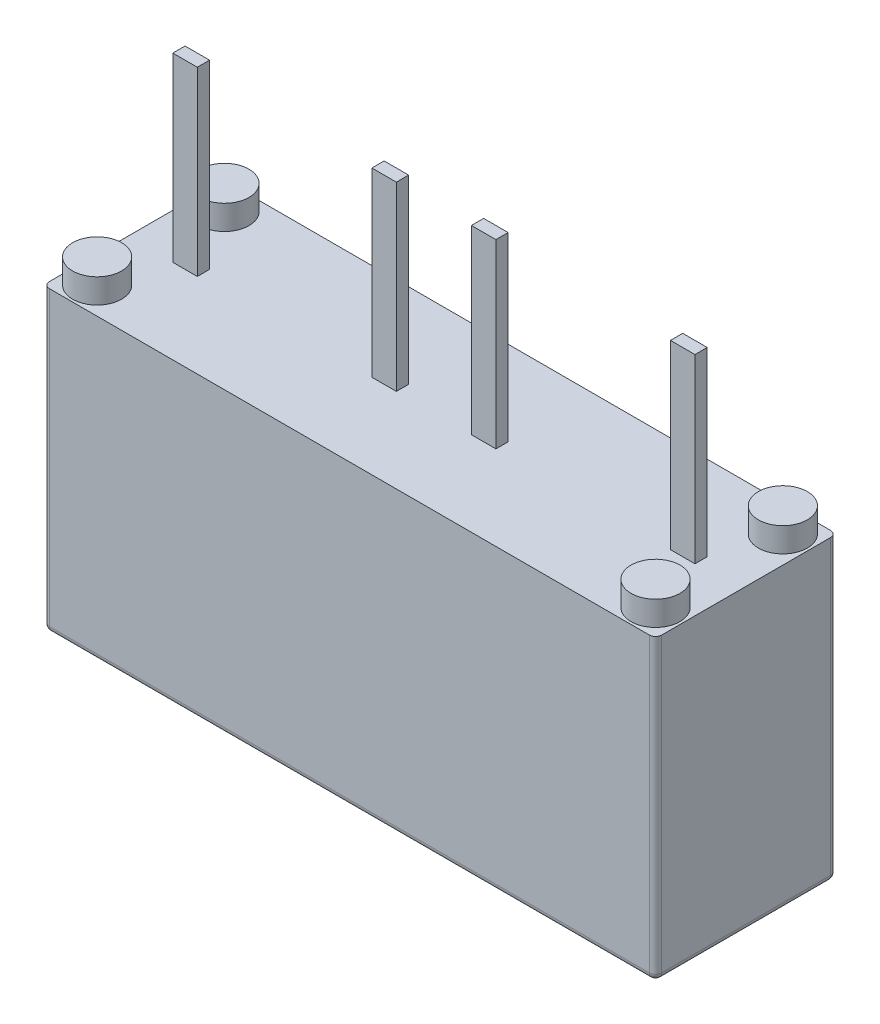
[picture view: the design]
from build123d import *

# Parameters (mm, degrees)
SKETCH1_W               = 12.5
SKETCH1_H               = 3.7
BOSS_EXTRUDE1_DEPTH     = 3.05
FILLET1_R               = 0.127
SKETCH12_R              = 0.625
BOSS_EXTRUDE8_DEPTH     = 0.001
SKETCH14_W              = 0.155844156
SKETCH14_H              = 1
BOSS_EXTRUDE10_DEPTH    = 0.001
SKETCH15_W              = 0.315584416
SKETCH15_H              = 0.175324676
SKETCH15_W_2            = 0.315584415
PART_NUMBER_DEPTH       = 0.001
SKETCH2_R               = 0.5
BOSS_EXTRUDE11_DEPTH    = 0.5
MIRROR2_COPY_1_SKETCH_R = 0.5
MIRROR2_COPY_1_DEPTH    = 0.5
SKETCH16_W              = 0.5
SKETCH16_H              = 0.25
BOSS_EXTRUDE12_DEPTH    = 3.7


with BuildPart() as part:
    # Sketch1 → Boss-Extrude1 (new, symmetric)
    with BuildSketch(Plane(origin=(0, 0, 0), x_dir=(1, 0, 0), z_dir=(0, 1, 0))):
        Rectangle(SKETCH1_W, SKETCH1_H)
    extrude(amount=BOSS_EXTRUDE1_DEPTH, both=True)

    # Fillet1
    fillet1_edges = [part.edges().sort_by_distance(p)[0] for p in [
        (0, -3.05, 1.85),
        (-6.25, -3.05, 0),
        (0, -3.05, -1.85),
        (6.25, -3.05, 0),
        (6.25, 0, 1.85),
        (-6.25, 0, 1.85),
        (-6.25, 0, -1.85),
        (6.25, 0, -1.85),
    ]]
    fillet(fillet1_edges, radius=FILLET1_R)

    # Sketch12 → Boss-Extrude8 (add)
    with BuildSketch(Plane(origin=(0, -3.05, 0), x_dir=(-1, 0, 0), z_dir=(0, -1, 0))):
        with Locations(Location((5.337664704, 0.725256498, 0), (0, 0, 270))):
            Circle(SKETCH12_R)
        Polygon((-4.767808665, 0.401887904), (-5.208078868, -1.480706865), (-5.548883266, -1.401005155), (-5.270390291, -0.21016959), (-5.767010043, -0.559917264), (-5.406669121, 0.980900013), (-5.650100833, 1.037829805), (-5.134766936, 1.287763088), (-4.82243301, 0.844268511), (-5.065864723, 0.901198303), (-5.264428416, 0.05214023), align=None)
    extrude(amount=BOSS_EXTRUDE8_DEPTH)

    # Sketch14 → Boss-Extrude10 (add)
    # profile 1 of 14: a face of its own
    with BuildSketch(Plane.XZ.offset(3.05)):
        with BuildLine():
            Line((-5.930411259, 0.573168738), (-5.930411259, 1.573168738))
            Line((-5.930411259, 1.573168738), (-5.66093074, 1.573168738))
            add(Edge.make_bspline(
                [(-5.66093074, 1.573168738), (-5.648958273, 1.573126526), (-5.626026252, 1.573045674), (-5.593279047, 1.572530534), (-5.563717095, 1.571269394), (-5.537463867, 1.569706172), (-5.514446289, 1.567732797), (-5.494757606, 1.565290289), (-5.478210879, 1.562725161), (-5.468474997, 1.559990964), (-5.464096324, 1.558761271)],
                knots=[0, 0, 0, 0, 1.45237712, 2.781878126, 3.972677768, 5.041396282, 5.972228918, 6.774219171, 7.448710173, 8, 8, 8, 8], degree=3))
            add(Edge.make_bspline(
                [(-5.464096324, 1.558761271), (-5.458035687, 1.556632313), (-5.445976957, 1.552396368), (-5.428545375, 1.544172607), (-5.411950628, 1.534267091), (-5.396234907, 1.522581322), (-5.381384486, 1.509322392), (-5.36727424, 1.494433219), (-5.354210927, 1.477745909), (-5.341744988, 1.459658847), (-5.330429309, 1.440110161), (-5.320602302, 1.419076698), (-5.312610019, 1.396588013), (-5.305600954, 1.372856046), (-5.300392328, 1.347670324), (-5.296808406, 1.321155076), (-5.294527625, 1.293311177), (-5.294210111, 1.274269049), (-5.294047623, 1.264524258)],
                knots=[0, 0, 0, 0, 0.846149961, 1.683567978, 2.535100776, 3.389102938, 4.260422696, 5.155850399, 6.088615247, 7.050446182, 8.048882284, 9.061856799, 10.105243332, 11.191356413, 12.320760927, 13.490669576, 14.715852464, 16, 16, 16, 16], degree=3))
            add(Edge.make_bspline(
                [(-5.294047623, 1.264524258), (-5.294140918, 1.255658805), (-5.294324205, 1.238241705), (-5.296460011, 1.212710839), (-5.299622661, 1.188233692), (-5.304251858, 1.164897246), (-5.310400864, 1.142690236), (-5.317714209, 1.121542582), (-5.326142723, 1.101380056), (-5.336162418, 1.082542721), (-5.347087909, 1.064969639), (-5.358701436, 1.048600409), (-5.370969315, 1.033669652), (-5.383990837, 1.020115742), (-5.397405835, 1.007634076), (-5.41196814, 0.997019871), (-5.426805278, 0.987285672), (-5.44280155, 0.97895084), (-5.460659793, 0.97204105), (-5.480917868, 0.965905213), (-5.504073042, 0.960956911), (-5.530105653, 0.956998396), (-5.559013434, 0.953784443), (-5.590753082, 0.951375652), (-5.625406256, 0.949955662), (-5.649430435, 0.949848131), (-5.66194535, 0.949792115)],
                knots=[0, 0, 0, 0, 1.135396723, 2.23060449, 3.279591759, 4.295786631, 5.275377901, 6.228987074, 7.160814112, 8.071657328, 8.958908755, 9.810053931, 10.641024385, 11.43162038, 12.216736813, 12.984447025, 13.736746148, 14.488596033, 15.289898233, 16.186242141, 17.197511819, 18.320073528, 19.558272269, 20.922626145, 22.396903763, 24, 24, 24, 24], degree=3))
            Line((-5.66194535, 0.949792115), (-5.774567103, 0.949792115))
            Line((-5.774567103, 0.949792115), (-5.774567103, 0.573168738))
            Line((-5.774567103, 0.573168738), (-5.930411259, 0.573168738))
        make_face()
        with BuildLine():
            Line((-5.774567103, 1.404337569), (-5.774567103, 1.118623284))
            Line((-5.774567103, 1.118623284), (-5.672903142, 1.118623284))
            add(Edge.make_bspline(
                [(-5.672903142, 1.118623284), (-5.6647182, 1.118658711), (-5.649022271, 1.118726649), (-5.626492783, 1.119334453), (-5.605989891, 1.120318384), (-5.587514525, 1.121717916), (-5.571124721, 1.123479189), (-5.556770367, 1.125722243), (-5.544473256, 1.128237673), (-5.530894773, 1.132247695), (-5.516006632, 1.139118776), (-5.499879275, 1.149669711), (-5.48546536, 1.162927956), (-5.47285882, 1.178593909), (-5.46245361, 1.19659899), (-5.455215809, 1.216812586), (-5.450561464, 1.238811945), (-5.450120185, 1.254150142), (-5.449891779, 1.262089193)],
                knots=[0, 0, 0, 0, 1.284283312, 2.462817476, 3.536098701, 4.504784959, 5.369772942, 6.121838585, 6.783804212, 7.337847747, 8.3400838, 9.343892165, 10.350558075, 11.399797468, 12.488501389, 13.596588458, 14.755994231, 16, 16, 16, 16], degree=3))
            add(Edge.make_bspline(
                [(-5.449891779, 1.262089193), (-5.450100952, 1.270167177), (-5.450505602, 1.285794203), (-5.455423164, 1.308112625), (-5.462764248, 1.328629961), (-5.47376598, 1.346580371), (-5.486416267, 1.362380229), (-5.500703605, 1.375710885), (-5.516814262, 1.385632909), (-5.531472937, 1.392009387), (-5.544933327, 1.395790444), (-5.557675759, 1.39782975), (-5.572833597, 1.399832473), (-5.590482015, 1.401725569), (-5.610595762, 1.402825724), (-5.633194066, 1.40357807), (-5.658289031, 1.404250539), (-5.67587882, 1.404307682), (-5.685078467, 1.404337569)],
                knots=[0, 0, 0, 0, 1.217310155, 2.3549115, 3.434183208, 4.491984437, 5.51587148, 6.484436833, 7.425091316, 8.358344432, 8.888574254, 9.53159621, 10.304262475, 11.197434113, 12.210261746, 13.34451227, 14.611151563, 16, 16, 16, 16], degree=3))
            Line((-5.685078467, 1.404337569), (-5.774567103, 1.404337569))
        make_face(mode=Mode.SUBTRACT)
    # profile 2 of 14: a face of its own
    with BuildSketch(Plane.XZ.offset(3.05)):
        with Locations((-5.086255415, 1.073168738)):
            Rectangle(SKETCH14_W, SKETCH14_H)
    # profile 3 of 14: a face of its own
    with BuildSketch(Plane.XZ.offset(3.05)):
        with BuildLine():
            Line((-4.320021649, 0.936805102), (-4.164177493, 0.871870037))
            add(Edge.make_bspline(
                [(-4.164177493, 0.871870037), (-4.167396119, 0.8587699), (-4.173667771, 0.833243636), (-4.185532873, 0.79675943), (-4.198589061, 0.762907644), (-4.213526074, 0.731877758), (-4.229831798, 0.703397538), (-4.24794414, 0.677747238), (-4.267522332, 0.654795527), (-4.288677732, 0.634596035), (-4.311376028, 0.617215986), (-4.334979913, 0.601728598), (-4.360098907, 0.589032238), (-4.386381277, 0.578312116), (-4.41403365, 0.570343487), (-4.44284593, 0.564346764), (-4.472941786, 0.56091516), (-4.493443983, 0.560428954), (-4.503869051, 0.560181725)],
                knots=[0, 0, 0, 0, 1.282586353, 2.499182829, 3.646034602, 4.730797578, 5.771318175, 6.763713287, 7.712684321, 8.6363956, 9.539720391, 10.428356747, 11.317388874, 12.212151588, 13.124116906, 14.050177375, 15.008543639, 16, 16, 16, 16], degree=3))
            add(Edge.make_bspline(
                [(-4.503869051, 0.560181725), (-4.516949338, 0.560475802), (-4.542573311, 0.561051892), (-4.579963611, 0.567250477), (-4.615543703, 0.576668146), (-4.64924945, 0.590191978), (-4.681120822, 0.607478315), (-4.710821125, 0.628889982), (-4.739043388, 0.653629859), (-4.755452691, 0.672919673), (-4.763812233, 0.68274666)],
                knots=[0, 0, 0, 0, 1.053414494, 2.063614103, 3.046293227, 4.01520277, 4.983805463, 5.961130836, 6.961320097, 8, 8, 8, 8], degree=3))
            add(Edge.make_bspline(
                [(-4.763812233, 0.68274666), (-4.77300105, 0.69487931), (-4.79151277, 0.719321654), (-4.814753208, 0.759627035), (-4.834519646, 0.802928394), (-4.850697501, 0.849264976), (-4.863307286, 0.898688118), (-4.872123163, 0.951221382), (-4.877417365, 1.006839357), (-4.878109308, 1.044950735), (-4.878463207, 1.064443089)],
                knots=[0, 0, 0, 0, 0.898140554, 1.809387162, 2.740718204, 3.705966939, 4.703925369, 5.74945803, 6.848943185, 8, 8, 8, 8], degree=3))
            add(Edge.make_bspline(
                [(-4.878463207, 1.064443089), (-4.878139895, 1.085020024), (-4.877510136, 1.125100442), (-4.871840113, 1.18345372), (-4.863196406, 1.238466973), (-4.850308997, 1.289935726), (-4.834164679, 1.338155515), (-4.81421842, 1.382825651), (-4.791058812, 1.424413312), (-4.77216322, 1.449250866), (-4.762797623, 1.461561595)],
                knots=[0, 0, 0, 0, 1.171098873, 2.281104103, 3.334483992, 4.338438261, 5.297974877, 6.225356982, 7.120398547, 8, 8, 8, 8], degree=3))
            add(Edge.make_bspline(
                [(-4.762797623, 1.461561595), (-4.754294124, 1.471512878), (-4.737535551, 1.491124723), (-4.708891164, 1.516520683), (-4.678118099, 1.538108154), (-4.64522749, 1.555782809), (-4.610072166, 1.569529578), (-4.572824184, 1.579229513), (-4.533334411, 1.584952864), (-4.506323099, 1.58574866), (-4.492505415, 1.586155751)],
                knots=[0, 0, 0, 0, 1.017460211, 2.005195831, 2.96880208, 3.936538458, 4.903086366, 5.898753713, 6.925103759, 8, 8, 8, 8], degree=3))
            add(Edge.make_bspline(
                [(-4.492505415, 1.586155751), (-4.481197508, 1.585885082), (-4.458972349, 1.585353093), (-4.426383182, 1.581100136), (-4.395333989, 1.573621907), (-4.365521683, 1.563812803), (-4.337207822, 1.550688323), (-4.310310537, 1.534762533), (-4.284724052, 1.516087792), (-4.269215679, 1.501569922), (-4.261377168, 1.49423205)],
                knots=[0, 0, 0, 0, 1.062174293, 2.087653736, 3.080296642, 4.058948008, 5.03139012, 6.005719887, 6.992016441, 8, 8, 8, 8], degree=3))
            add(Edge.make_bspline(
                [(-4.261377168, 1.49423205), (-4.255927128, 1.488576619), (-4.244821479, 1.477052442), (-4.229867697, 1.457640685), (-4.21602309, 1.436262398), (-4.203535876, 1.412826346), (-4.19192691, 1.387561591), (-4.181370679, 1.360338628), (-4.172084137, 1.331095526), (-4.166853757, 1.310817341), (-4.164177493, 1.300441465)],
                knots=[0, 0, 0, 0, 0.858002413, 1.748367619, 2.673305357, 3.63929672, 4.648357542, 5.711115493, 6.828831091, 8, 8, 8, 8], degree=3))
            Line((-4.164177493, 1.300441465), (-4.320021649, 1.248493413))
            add(Edge.make_bspline(
                [(-4.320021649, 1.248493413), (-4.321486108, 1.25514464), (-4.324335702, 1.268086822), (-4.330056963, 1.286764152), (-4.337022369, 1.304111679), (-4.344600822, 1.320545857), (-4.353726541, 1.335498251), (-4.36327233, 1.349683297), (-4.374465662, 1.362250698), (-4.386291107, 1.373860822), (-4.399165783, 1.383893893), (-4.412344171, 1.39296724), (-4.426219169, 1.400511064), (-4.440732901, 1.406578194), (-4.455713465, 1.411488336), (-4.471272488, 1.414941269), (-4.487374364, 1.417032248), (-4.498316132, 1.417226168), (-4.503869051, 1.417324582)],
                knots=[0, 0, 0, 0, 1.200071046, 2.335138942, 3.437621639, 4.493482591, 5.51985659, 6.521917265, 7.50210956, 8.480124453, 9.438987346, 10.374745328, 11.297656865, 12.216555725, 13.143999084, 14.072438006, 15.021767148, 16, 16, 16, 16], degree=3))
            add(Edge.make_bspline(
                [(-4.503869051, 1.417324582), (-4.511727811, 1.417091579), (-4.527194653, 1.416633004), (-4.549854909, 1.412984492), (-4.571294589, 1.406531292), (-4.591836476, 1.398059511), (-4.611135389, 1.386772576), (-4.62940617, 1.373103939), (-4.646157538, 1.356640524), (-4.662211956, 1.338122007), (-4.676759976, 1.316665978), (-4.689112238, 1.291868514), (-4.699300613, 1.263818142), (-4.708076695, 1.232716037), (-4.714642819, 1.198357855), (-4.719199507, 1.160796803), (-4.722043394, 1.120087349), (-4.722422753, 1.091842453), (-4.722619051, 1.07722718)],
                knots=[0, 0, 0, 0, 0.827686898, 1.628972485, 2.409099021, 3.181967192, 3.964173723, 4.757978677, 5.579415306, 6.433460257, 7.33665582, 8.302235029, 9.343905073, 10.476376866, 11.703364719, 13.024698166, 14.460435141, 16, 16, 16, 16], degree=3))
            add(Edge.make_bspline(
                [(-4.722619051, 1.07722718), (-4.722397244, 1.062072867), (-4.72197011, 1.03289025), (-4.719480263, 0.990740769), (-4.714747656, 0.95201505), (-4.708689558, 0.916560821), (-4.700399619, 0.884585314), (-4.690271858, 0.856068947), (-4.678606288, 0.830733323), (-4.664690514, 0.808910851), (-4.649271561, 0.79007156), (-4.632878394, 0.773714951), (-4.615194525, 0.76005128), (-4.596693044, 0.748471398), (-4.57686601, 0.73969647), (-4.555947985, 0.733726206), (-4.534063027, 0.729596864), (-4.519040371, 0.729210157), (-4.511377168, 0.729012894)],
                knots=[0, 0, 0, 0, 1.588381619, 3.058741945, 4.422565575, 5.675514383, 6.825848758, 7.879737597, 8.8437938, 9.742560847, 10.584031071, 11.391113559, 12.163968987, 12.921455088, 13.673648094, 14.427376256, 15.197789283, 16, 16, 16, 16], degree=3))
            add(Edge.make_bspline(
                [(-4.511377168, 0.729012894), (-4.505756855, 0.729186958), (-4.49460773, 0.729532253), (-4.478201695, 0.731730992), (-4.462370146, 0.735662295), (-4.447110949, 0.741116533), (-4.432489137, 0.748312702), (-4.41835469, 0.756838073), (-4.404993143, 0.767085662), (-4.392057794, 0.778721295), (-4.379857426, 0.79210433), (-4.368707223, 0.807491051), (-4.358347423, 0.824606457), (-4.348840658, 0.843556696), (-4.340126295, 0.864219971), (-4.332442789, 0.886754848), (-4.325489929, 0.911048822), (-4.321879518, 0.928054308), (-4.320021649, 0.936805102)],
                knots=[0, 0, 0, 0, 0.874040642, 1.73385169, 2.568061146, 3.406503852, 4.248567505, 5.09821747, 5.96915136, 6.862782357, 7.800986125, 8.779254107, 9.812897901, 10.908933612, 12.073249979, 13.297367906, 14.609261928, 16, 16, 16, 16], degree=3))
        make_face()
    # profile 4 of 14: a face of its own
    with BuildSketch(Plane.XZ.offset(3.05)):
        Polygon((-4.008333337, 0.573168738), (-4.008333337, 1.573168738), (-3.852489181, 1.573168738), (-3.852489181, 1.091837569), (-3.472416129, 1.573168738), (-3.274567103, 1.573168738), (-3.58869048, 1.192081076), (-3.26158009, 0.573168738), (-3.481953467, 0.573168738), (-3.709632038, 1.045165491), (-3.852489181, 0.871870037), (-3.852489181, 0.573168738), align=None)
    # profile 5 of 14: a face of its own
    with BuildSketch(Plane.XZ.offset(3.05)):
        Polygon((-3.177164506, 0.573168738), (-3.177164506, 1.573168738), (-2.566774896, 1.573168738), (-2.566774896, 1.404337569), (-3.02132035, 1.404337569), (-3.02132035, 1.170571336), (-2.592748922, 1.170571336), (-2.592748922, 1.01472718), (-3.02132035, 1.01472718), (-3.02132035, 0.741999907), (-2.553787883, 0.741999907), (-2.553787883, 0.573168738), align=None)
    # profile 6 of 14: a face of its own
    with BuildSketch(Plane.XZ.offset(3.05)):
        with BuildLine():
            Line((-2.41093074, 0.573168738), (-2.41093074, 1.573168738))
            Line((-2.41093074, 1.573168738), (-2.059875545, 1.573168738))
            add(Edge.make_bspline(
                [(-2.059875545, 1.573168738), (-2.049052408, 1.573089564), (-2.028210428, 1.5729371), (-1.998082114, 1.571814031), (-1.97041902, 1.569488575), (-1.945064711, 1.566810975), (-1.922235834, 1.56298159), (-1.901765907, 1.558324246), (-1.883682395, 1.552948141), (-1.862708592, 1.544587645), (-1.839208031, 1.530753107), (-1.813936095, 1.50953802), (-1.791453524, 1.48325734), (-1.771718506, 1.452520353), (-1.755427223, 1.41764306), (-1.744003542, 1.37900532), (-1.736664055, 1.337178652), (-1.735965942, 1.308117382), (-1.735606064, 1.293136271)],
                knots=[0, 0, 0, 0, 1.04688713, 2.015977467, 2.915189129, 3.731617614, 4.481301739, 5.152637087, 5.761127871, 6.304197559, 7.333207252, 8.382830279, 9.482073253, 10.665313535, 11.906396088, 13.191683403, 14.552310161, 16, 16, 16, 16], degree=3))
            add(Edge.make_bspline(
                [(-1.735606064, 1.293136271), (-1.735828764, 1.283593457), (-1.736263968, 1.264944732), (-1.73884566, 1.237658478), (-1.743453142, 1.211771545), (-1.750266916, 1.187401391), (-1.758462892, 1.164271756), (-1.768911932, 1.142707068), (-1.781111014, 1.122505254), (-1.795132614, 1.103826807), (-1.810822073, 1.086684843), (-1.828173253, 1.071214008), (-1.847069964, 1.057303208), (-1.867759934, 1.045452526), (-1.889690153, 1.034714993), (-1.913401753, 1.026103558), (-1.938621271, 1.018902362), (-1.956150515, 1.015602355), (-1.965110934, 1.013915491)],
                knots=[0, 0, 0, 0, 1.148725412, 2.24485837, 3.2956961, 4.308991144, 5.287710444, 6.245445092, 7.187969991, 8.124285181, 9.052065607, 9.980417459, 10.918430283, 11.870785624, 12.846723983, 13.853982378, 14.9030207, 16, 16, 16, 16], degree=3))
            add(Edge.make_bspline(
                [(-1.965110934, 1.013915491), (-1.956227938, 1.00760899), (-1.938847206, 0.995269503), (-1.914789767, 0.975096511), (-1.893269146, 0.953953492), (-1.87678348, 0.935244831), (-1.864346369, 0.918539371), (-1.853991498, 0.903972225), (-1.842876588, 0.887089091), (-1.830857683, 0.867968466), (-1.81815825, 0.846469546), (-1.804561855, 0.82272515), (-1.790133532, 0.796654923), (-1.780300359, 0.778467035), (-1.77517587, 0.768988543)],
                knots=[0, 0, 0, 0, 1.250008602, 2.445803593, 3.598666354, 4.710220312, 5.303348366, 5.98833631, 6.761333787, 7.622934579, 8.580231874, 9.626942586, 10.763297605, 12, 12, 12, 12], degree=3))
            Line((-1.77517587, 0.768988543), (-1.670670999, 0.573168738))
            Line((-1.670670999, 0.573168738), (-1.889623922, 0.573168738))
            Line((-1.889623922, 0.573168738), (-2.005492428, 0.789483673))
            add(Edge.make_bspline(
                [(-2.005492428, 0.789483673), (-2.010478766, 0.79882835), (-2.019968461, 0.816612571), (-2.033802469, 0.841825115), (-2.046374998, 0.864248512), (-2.057485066, 0.88410925), (-2.067648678, 0.900999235), (-2.076324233, 0.915392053), (-2.083983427, 0.926848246), (-2.092248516, 0.938422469), (-2.101899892, 0.950064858), (-2.113970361, 0.961556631), (-2.126316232, 0.970811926), (-2.13963391, 0.977907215), (-2.155052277, 0.98324112), (-2.173823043, 0.986249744), (-2.196313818, 0.9886272), (-2.212599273, 0.988708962), (-2.221401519, 0.988753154)],
                knots=[0, 0, 0, 0, 1.60136501, 3.047620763, 4.347844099, 5.488187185, 6.487883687, 7.328020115, 8.028596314, 8.570701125, 9.478104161, 10.309984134, 11.085182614, 11.803449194, 12.582885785, 13.539658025, 14.670191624, 16, 16, 16, 16], degree=3))
            Line((-2.221401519, 0.988753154), (-2.255086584, 0.988753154))
            Line((-2.255086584, 0.988753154), (-2.255086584, 0.573168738))
            Line((-2.255086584, 0.573168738), (-2.41093074, 0.573168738))
        make_face()
        with BuildLine():
            Line((-2.255086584, 1.157584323), (-2.121766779, 1.157584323))
            add(Edge.make_bspline(
                [(-2.121766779, 1.157584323), (-2.112026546, 1.157641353), (-2.093492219, 1.157749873), (-2.067106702, 1.158068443), (-2.043500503, 1.158929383), (-2.022730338, 1.159904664), (-2.004657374, 1.161078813), (-1.98940683, 1.162581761), (-1.976885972, 1.164631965), (-1.963951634, 1.167453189), (-1.950238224, 1.172664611), (-1.935818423, 1.181423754), (-1.922757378, 1.192278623), (-1.911591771, 1.205832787), (-1.902300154, 1.221788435), (-1.895924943, 1.240323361), (-1.891990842, 1.26117861), (-1.891636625, 1.275868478), (-1.89145022, 1.283598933)],
                knots=[0, 0, 0, 0, 1.530151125, 2.911667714, 4.144992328, 5.240737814, 6.177978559, 6.99000054, 7.646825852, 8.170085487, 9.068012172, 9.935431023, 10.810237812, 11.723128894, 12.67998143, 13.694953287, 14.786982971, 16, 16, 16, 16], degree=3))
            add(Edge.make_bspline(
                [(-1.89145022, 1.283598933), (-1.891646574, 1.290989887), (-1.892022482, 1.305139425), (-1.895878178, 1.325214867), (-1.902361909, 1.343040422), (-1.911624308, 1.35846041), (-1.923113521, 1.37148697), (-1.936397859, 1.382539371), (-1.951618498, 1.391353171), (-1.962867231, 1.395123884), (-1.96856061, 1.397032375)],
                knots=[0, 0, 0, 0, 1.194031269, 2.285901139, 3.289564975, 4.246236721, 5.176404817, 6.085300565, 7.030903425, 8, 8, 8, 8], degree=3))
            add(Edge.make_bspline(
                [(-1.96856061, 1.397032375), (-1.971125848, 1.397599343), (-1.977231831, 1.398948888), (-1.987998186, 1.400531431), (-2.001827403, 1.40161214), (-2.018605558, 1.402623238), (-2.038361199, 1.403391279), (-2.061088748, 1.404058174), (-2.086796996, 1.404111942), (-2.10492442, 1.404259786), (-2.114461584, 1.404337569)],
                knots=[0, 0, 0, 0, 0.430892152, 1.025643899, 1.783105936, 2.70574662, 3.782977, 5.026178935, 6.435419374, 8, 8, 8, 8], degree=3))
            Line((-2.114461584, 1.404337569), (-2.255086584, 1.404337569))
            Line((-2.255086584, 1.404337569), (-2.255086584, 1.157584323))
        make_face(mode=Mode.SUBTRACT)
    # profile 7 of 14: a face of its own
    with BuildSketch(Plane.XZ.offset(3.05)):
        with Locations((-1.501839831, 1.073168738)):
            Rectangle(SKETCH14_W, SKETCH14_H)
    # profile 8 of 14: a face of its own
    with BuildSketch(Plane.XZ.offset(3.05)):
        Polygon((-1.255086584, 0.573168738), (-1.255086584, 1.573168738), (-1.092343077, 1.573168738), (-0.748593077, 0.90535218), (-0.748593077, 1.573168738), (-0.592748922, 1.573168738), (-0.592748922, 0.573168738), (-0.761174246, 0.573168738), (-1.099242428, 1.225360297), (-1.099242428, 0.573168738), align=None)
    # profile 9 of 14: a face of its own
    with BuildSketch(Plane.XZ.offset(3.05)):
        with BuildLine():
            Line((-0.047294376, 0.936805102), (-0.047294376, 1.105636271))
            Line((-0.047294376, 1.105636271), (0.303354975, 1.105636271))
            Line((0.303354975, 1.105636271), (0.303354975, 0.712779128))
            add(Edge.make_bspline(
                [(0.303354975, 0.712779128), (0.298682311, 0.707579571), (0.289244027, 0.697077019), (0.273700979, 0.682169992), (0.256630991, 0.668000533), (0.238092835, 0.654476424), (0.21832226, 0.641171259), (0.197148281, 0.628458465), (0.174398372, 0.616459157), (0.142672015, 0.601230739), (0.101918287, 0.584842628), (0.052118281, 0.570859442), (0.002276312, 0.561819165), (-0.031090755, 0.560725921), (-0.04770022, 0.560181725)],
                knots=[0, 0, 0, 0, 0.640095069, 1.292924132, 1.970305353, 2.670365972, 3.393721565, 4.15229731, 4.931044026, 5.748453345, 7.375093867, 8.945946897, 10.479752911, 12, 12, 12, 12], degree=3))
            add(Edge.make_bspline(
                [(-0.04770022, 0.560181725), (-0.057648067, 0.560409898), (-0.07730736, 0.56086082), (-0.106414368, 0.563444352), (-0.134608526, 0.568149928), (-0.161885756, 0.574605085), (-0.188228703, 0.583049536), (-0.21383544, 0.593055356), (-0.238333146, 0.605385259), (-0.262087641, 0.619112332), (-0.284504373, 0.635095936), (-0.306194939, 0.652425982), (-0.326274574, 0.672072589), (-0.345115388, 0.693480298), (-0.363126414, 0.716458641), (-0.379741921, 0.741424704), (-0.394901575, 0.768390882), (-0.409122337, 0.796915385), (-0.421894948, 0.827038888), (-0.432783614, 0.858603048), (-0.442223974, 0.891353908), (-0.449640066, 0.925540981), (-0.455498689, 0.960965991), (-0.459731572, 0.997669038), (-0.462488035, 1.035653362), (-0.462747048, 1.061461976), (-0.462878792, 1.074589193)],
                knots=[0, 0, 0, 0, 0.96294793, 1.903012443, 2.825402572, 3.727352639, 4.613530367, 5.501013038, 6.385229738, 7.265535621, 8.153718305, 9.047361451, 9.95019023, 10.868482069, 11.806149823, 12.77395942, 13.767900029, 14.798508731, 15.857606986, 16.932193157, 18.028419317, 19.154653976, 20.31598268, 21.50241393, 22.729635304, 24, 24, 24, 24], degree=3))
            add(Edge.make_bspline(
                [(-0.462878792, 1.074589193), (-0.46274577, 1.087986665), (-0.46248416, 1.114335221), (-0.459748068, 1.153066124), (-0.455483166, 1.190370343), (-0.449768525, 1.226182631), (-0.441894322, 1.260482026), (-0.432730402, 1.293351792), (-0.421463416, 1.324683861), (-0.408726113, 1.35450231), (-0.394513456, 1.382632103), (-0.379298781, 1.409070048), (-0.363136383, 1.433683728), (-0.345721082, 1.456291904), (-0.327593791, 1.477273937), (-0.308111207, 1.49617588), (-0.287933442, 1.513550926), (-0.26640474, 1.528733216), (-0.244121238, 1.542539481), (-0.220413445, 1.553970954), (-0.195854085, 1.564011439), (-0.170134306, 1.572140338), (-0.143334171, 1.578425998), (-0.115448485, 1.582769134), (-0.086593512, 1.585822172), (-0.066986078, 1.586043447), (-0.057034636, 1.586155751)],
                knots=[0, 0, 0, 0, 1.312030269, 2.580345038, 3.800688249, 4.988959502, 6.130087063, 7.24577612, 8.3291513, 9.388705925, 10.419771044, 11.414082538, 12.375082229, 13.301312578, 14.207494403, 15.088254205, 15.957754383, 16.812618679, 17.66591557, 18.52219064, 19.38705966, 20.262872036, 21.161173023, 22.080434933, 23.025755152, 24, 24, 24, 24], degree=3))
            add(Edge.make_bspline(
                [(-0.057034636, 1.586155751), (-0.045121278, 1.585929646), (-0.021912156, 1.585489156), (0.012045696, 1.58183497), (0.044100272, 1.575460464), (0.074506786, 1.567143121), (0.102902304, 1.555773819), (0.129668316, 1.542261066), (0.154430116, 1.525875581), (0.177544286, 1.507345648), (0.198733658, 1.486364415), (0.217842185, 1.462917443), (0.234878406, 1.437151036), (0.250284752, 1.409300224), (0.263073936, 1.378764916), (0.27456124, 1.346182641), (0.283615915, 1.31111288), (0.288081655, 1.286875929), (0.290367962, 1.274467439)],
                knots=[0, 0, 0, 0, 1.106718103, 2.156063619, 3.167949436, 4.140832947, 5.080279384, 6.00497985, 6.921830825, 7.833627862, 8.753510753, 9.686947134, 10.638631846, 11.620184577, 12.639304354, 13.710570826, 14.827890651, 16, 16, 16, 16], degree=3))
            Line((0.290367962, 1.274467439), (0.134523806, 1.248493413))
            add(Edge.make_bspline(
                [(0.134523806, 1.248493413), (0.132849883, 1.255145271), (0.129573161, 1.26816636), (0.123317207, 1.286939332), (0.115660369, 1.304386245), (0.107508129, 1.320861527), (0.098087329, 1.335981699), (0.087643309, 1.349847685), (0.076379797, 1.362685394), (0.06389533, 1.374050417), (0.050682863, 1.384156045), (0.036969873, 1.393234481), (0.022319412, 1.400403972), (0.007407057, 1.406911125), (-0.008387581, 1.411434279), (-0.024705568, 1.414980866), (-0.041696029, 1.417014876), (-0.053241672, 1.41722076), (-0.059063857, 1.417324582)],
                knots=[0, 0, 0, 0, 1.177468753, 2.304908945, 3.392157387, 4.44646936, 5.458353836, 6.445477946, 7.424370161, 8.386026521, 9.338381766, 10.278981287, 11.203455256, 12.135194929, 13.068453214, 14.018255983, 15.000655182, 16, 16, 16, 16], degree=3))
            add(Edge.make_bspline(
                [(-0.059063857, 1.417324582), (-0.06807356, 1.417112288), (-0.085773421, 1.416695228), (-0.111647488, 1.412775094), (-0.136173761, 1.406206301), (-0.1594658, 1.397336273), (-0.181365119, 1.385609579), (-0.201906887, 1.371353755), (-0.221124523, 1.354508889), (-0.239045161, 1.335257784), (-0.255115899, 1.313194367), (-0.26916576, 1.288504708), (-0.280923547, 1.261127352), (-0.29040858, 1.231055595), (-0.297855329, 1.198267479), (-0.303257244, 1.162805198), (-0.306551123, 1.124638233), (-0.306869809, 1.098337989), (-0.307034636, 1.084735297)],
                knots=[0, 0, 0, 0, 0.921848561, 1.811002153, 2.670935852, 3.517043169, 4.356494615, 5.20737657, 6.07109315, 6.967737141, 7.894254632, 8.858726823, 9.869747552, 10.938357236, 12.082205, 13.308268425, 14.607815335, 16, 16, 16, 16], degree=3))
            add(Edge.make_bspline(
                [(-0.307034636, 1.084735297), (-0.306798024, 1.070117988), (-0.306339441, 1.041787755), (-0.302893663, 1.000636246), (-0.297106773, 0.962165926), (-0.288775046, 0.926357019), (-0.278324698, 0.893178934), (-0.265482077, 0.862720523), (-0.250453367, 0.834822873), (-0.238046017, 0.818296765), (-0.231953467, 0.810181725)],
                knots=[0, 0, 0, 0, 1.209924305, 2.344989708, 3.415650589, 4.427521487, 5.38553267, 6.291346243, 7.16097645, 8, 8, 8, 8], degree=3))
            add(Edge.make_bspline(
                [(-0.231953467, 0.810181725), (-0.226494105, 0.803675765), (-0.215763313, 0.790887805), (-0.19723048, 0.774499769), (-0.177683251, 0.760183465), (-0.156362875, 0.748879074), (-0.133736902, 0.739812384), (-0.109582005, 0.733641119), (-0.084091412, 0.729609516), (-0.066588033, 0.72921467), (-0.057643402, 0.729012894)],
                knots=[0, 0, 0, 0, 1.020747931, 2.006357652, 2.968701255, 3.930183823, 4.9021189, 5.895229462, 6.924413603, 8, 8, 8, 8], degree=3))
            add(Edge.make_bspline(
                [(-0.057643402, 0.729012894), (-0.049035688, 0.729292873), (-0.031516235, 0.729862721), (-0.005101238, 0.734403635), (0.021866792, 0.741317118), (0.049048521, 0.751002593), (0.075656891, 0.763294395), (0.101270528, 0.777521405), (0.125261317, 0.793978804), (0.140098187, 0.806407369), (0.147510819, 0.81261679)],
                knots=[0, 0, 0, 0, 0.913346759, 1.858953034, 2.837757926, 3.866620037, 4.917326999, 5.946088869, 6.973847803, 8, 8, 8, 8], degree=3))
            Line((0.147510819, 0.81261679), (0.147510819, 0.936805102))
            Line((0.147510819, 0.936805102), (-0.047294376, 0.936805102))
        make_face()
    # profile 10 of 14: a face of its own
    with BuildSketch(Plane.XZ.offset(3.05)):
        Polygon((1.306378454, 0.573168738), (1.098383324, 1.573168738), (1.256865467, 1.573168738), (1.390591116, 0.881204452), (1.534259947, 1.573168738), (1.741037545, 1.573168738), (1.88409761, 0.868217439), (2.017823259, 1.573168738), (2.176305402, 1.573168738), (1.971557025, 0.573168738), (1.79034761, 0.573168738), (1.637344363, 1.32722718), (1.480891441, 0.573168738), align=None)
    # profile 11 of 14: a face of its own
    with BuildSketch(Plane.XZ.offset(3.05)):
        Polygon((2.343837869, 0.573168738), (2.343837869, 1.573168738), (2.499682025, 1.573168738), (2.499682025, 1.05084731), (2.699966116, 1.300441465), (2.895785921, 1.300441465), (2.685761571, 1.039077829), (2.908772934, 0.573168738), (2.740550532, 0.573168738), (2.580445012, 0.907381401), (2.499682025, 0.806934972), (2.499682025, 0.573168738), align=None)
    # profile 12 of 14: a face of its own
    with BuildSketch(Plane.XZ.offset(3.05)):
        Polygon((2.965915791, 0.560181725), (3.17086709, 1.586155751), (3.303578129, 1.586155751), (3.09862683, 0.560181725), align=None)
    # profile 13 of 14: a face of its own
    with BuildSketch(Plane.XZ.offset(3.05)):
        Polygon((3.678902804, 0.573168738), (3.678902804, 0.985100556), (3.380201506, 1.573168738), (3.553699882, 1.573168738), (3.764535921, 1.164686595), (3.960152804, 1.573168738), (4.133448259, 1.573168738), (3.83474696, 0.983680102), (3.83474696, 0.573168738), align=None)
    # profile 14 of 14: a face of its own
    with BuildSketch(Plane.XZ.offset(3.05)):
        with BuildLine():
            Line((4.456824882, 0.573168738), (4.300980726, 0.573168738))
            Line((4.300980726, 0.573168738), (4.300980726, 1.300441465))
            Line((4.300980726, 1.300441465), (4.443837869, 1.300441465))
            Line((4.443837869, 1.300441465), (4.443837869, 1.197154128))
            add(Edge.make_bspline(
                [(4.443837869, 1.197154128), (4.446864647, 1.202912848), (4.45269446, 1.214004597), (4.461366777, 1.229835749), (4.469805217, 1.244159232), (4.478419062, 1.256555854), (4.486219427, 1.267770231), (4.49422271, 1.277088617), (4.501829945, 1.285010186), (4.511527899, 1.293439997), (4.52435564, 1.301425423), (4.54074876, 1.308477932), (4.558425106, 1.312589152), (4.570575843, 1.313145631), (4.57675183, 1.313428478)],
                knots=[0, 0, 0, 0, 1.247976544, 2.403700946, 3.462962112, 4.43467857, 5.299009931, 6.081551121, 6.788109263, 7.404564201, 8.542080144, 9.670008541, 10.815710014, 12, 12, 12, 12], degree=3))
            add(Edge.make_bspline(
                [(4.57675183, 1.313428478), (4.58552824, 1.313026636), (4.603086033, 1.312222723), (4.62887778, 1.304746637), (4.654167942, 1.293435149), (4.669644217, 1.282651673), (4.677604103, 1.277105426)],
                knots=[0, 0, 0, 0, 0.96387831, 1.928302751, 2.934467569, 4, 4, 4, 4], degree=3))
            Line((4.677604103, 1.277105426), (4.628294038, 1.113144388))
            add(Edge.make_bspline(
                [(4.628294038, 1.113144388), (4.622276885, 1.117950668), (4.610903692, 1.127035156), (4.592616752, 1.136807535), (4.574881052, 1.143288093), (4.563002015, 1.144171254), (4.557271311, 1.14459731)],
                knots=[0, 0, 0, 0, 1.164920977, 2.201850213, 3.13253367, 4, 4, 4, 4], degree=3))
            add(Edge.make_bspline(
                [(4.557271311, 1.14459731), (4.552157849, 1.144365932), (4.541978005, 1.143905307), (4.527384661, 1.138881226), (4.513642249, 1.131274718), (4.501000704, 1.120154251), (4.48949515, 1.105106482), (4.480441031, 1.084993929), (4.472613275, 1.060363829), (4.467774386, 1.036236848), (4.464730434, 1.013476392), (4.46247672, 0.992506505), (4.460713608, 0.968208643), (4.459379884, 0.94059977), (4.458107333, 0.909689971), (4.457335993, 0.875390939), (4.456986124, 0.837712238), (4.456880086, 0.811466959), (4.456824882, 0.797803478)],
                knots=[0, 0, 0, 0, 0.622595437, 1.239458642, 1.864845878, 2.532755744, 3.28162568, 4.161487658, 5.21226045, 6.436118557, 7.162012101, 8.018184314, 9.012812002, 10.138387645, 11.395699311, 12.792934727, 14.330378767, 16, 16, 16, 16], degree=3))
            Line((4.456824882, 0.797803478), (4.456824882, 0.573168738))
        make_face()
    extrude(amount=BOSS_EXTRUDE10_DEPTH)

    # Sketch15 → Part Number (add)
    # profile 1 of 13: a face of its own
    with BuildSketch(Plane.XZ.offset(3.05)):
        with BuildLine():
            Line((-4.109090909, -1.323), (-4.284415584, -1.323))
            Line((-4.284415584, -1.323), (-4.284415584, -0.668454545))
            add(Edge.make_bspline(
                [(-4.284415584, -0.668454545), (-4.292496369, -0.675607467), (-4.308602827, -0.689864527), (-4.334109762, -0.709600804), (-4.360502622, -0.727843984), (-4.387974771, -0.744497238), (-4.416094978, -0.760044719), (-4.44532349, -0.773957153), (-4.475427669, -0.786437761), (-4.496103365, -0.793484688), (-4.506493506, -0.797025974)],
                knots=[0, 0, 0, 0, 1.001509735, 1.996189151, 2.991510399, 3.978083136, 4.977007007, 5.972841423, 6.981293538, 8, 8, 8, 8], degree=3))
            Line((-4.506493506, -0.797025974), (-4.506493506, -0.645077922))
            add(Edge.make_bspline(
                [(-4.506493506, -0.645077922), (-4.494219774, -0.640626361), (-4.468960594, -0.631465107), (-4.431731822, -0.612610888), (-4.39395177, -0.589286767), (-4.362631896, -0.566639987), (-4.338134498, -0.546622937), (-4.320940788, -0.530700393), (-4.305125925, -0.514239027), (-4.290935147, -0.497126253), (-4.278207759, -0.479411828), (-4.266926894, -0.461260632), (-4.257065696, -0.442489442), (-4.251802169, -0.429500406), (-4.249168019, -0.423)],
                knots=[0, 0, 0, 0, 1.342253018, 2.762339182, 4.28336265, 5.906997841, 6.73458361, 7.536776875, 8.316428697, 9.08145313, 9.821906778, 10.558829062, 11.278761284, 12, 12, 12, 12], degree=3))
            Line((-4.249168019, -0.423), (-4.109090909, -0.423))
            Line((-4.109090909, -0.423), (-4.109090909, -1.323))
        make_face()
    # profile 2 of 13: a face of its own
    with BuildSketch(Plane.XZ.offset(3.05)):
        with BuildLine():
            Line((-3.793506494, -1.089233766), (-3.618181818, -1.065857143))
            add(Edge.make_bspline(
                [(-3.618181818, -1.065857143), (-3.616929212, -1.075706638), (-3.614545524, -1.094450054), (-3.606938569, -1.120551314), (-3.595855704, -1.142942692), (-3.581793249, -1.161575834), (-3.56519132, -1.176118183), (-3.547075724, -1.186774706), (-3.527371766, -1.193377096), (-3.51370674, -1.19407479), (-3.506777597, -1.194428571)],
                knots=[0, 0, 0, 0, 1.267629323, 2.412276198, 3.456104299, 4.444224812, 5.375938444, 6.257992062, 7.116677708, 8, 8, 8, 8], degree=3))
            add(Edge.make_bspline(
                [(-3.506777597, -1.194428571), (-3.502992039, -1.194359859), (-3.495486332, -1.194223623), (-3.484491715, -1.192017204), (-3.473849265, -1.189014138), (-3.463712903, -1.184586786), (-3.454193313, -1.178795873), (-3.444895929, -1.172025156), (-3.436255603, -1.163759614), (-3.427933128, -1.154447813), (-3.420551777, -1.143860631), (-3.41390365, -1.132354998), (-3.408486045, -1.119814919), (-3.403819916, -1.106416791), (-3.400476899, -1.091949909), (-3.397863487, -1.076590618), (-3.39645343, -1.060282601), (-3.396222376, -1.049118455), (-3.396103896, -1.043393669)],
                knots=[0, 0, 0, 0, 0.867416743, 1.719845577, 2.564449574, 3.403020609, 4.249010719, 5.118226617, 6.037663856, 6.988117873, 7.980682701, 8.994658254, 10.033274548, 11.111557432, 12.247002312, 13.437030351, 14.685752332, 16, 16, 16, 16], degree=3))
            add(Edge.make_bspline(
                [(-3.396103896, -1.043393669), (-3.396486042, -1.032959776), (-3.397211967, -1.013139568), (-3.402731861, -0.985008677), (-3.412713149, -0.960520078), (-3.426190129, -0.93973362), (-3.44251758, -0.923203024), (-3.460697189, -0.910817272), (-3.481000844, -0.903600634), (-3.495096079, -0.902683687), (-3.502211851, -0.902220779)],
                knots=[0, 0, 0, 0, 1.270953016, 2.414300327, 3.472121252, 4.473984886, 5.412803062, 6.285035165, 7.134225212, 8, 8, 8, 8], degree=3))
            add(Edge.make_bspline(
                [(-3.502211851, -0.902220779), (-3.507275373, -0.902346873), (-3.517949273, -0.902612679), (-3.5345764, -0.905503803), (-3.552672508, -0.909388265), (-3.565001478, -0.913200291), (-3.571428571, -0.9151875)],
                knots=[0, 0, 0, 0, 0.85882803, 1.81040837, 2.8585658, 4, 4, 4, 4], degree=3))
            Line((-3.571428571, -0.9151875), (-3.553165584, -0.761961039))
            add(Edge.make_bspline(
                [(-3.553165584, -0.761961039), (-3.543336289, -0.761837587), (-3.524630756, -0.761602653), (-3.498162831, -0.756534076), (-3.47449332, -0.748317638), (-3.461323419, -0.73919244), (-3.454910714, -0.734749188)],
                knots=[0, 0, 0, 0, 1.133310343, 2.15673376, 3.102474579, 4, 4, 4, 4], degree=3))
            add(Edge.make_bspline(
                [(-3.454910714, -0.734749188), (-3.449442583, -0.729826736), (-3.438568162, -0.720037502), (-3.427392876, -0.70071351), (-3.420566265, -0.678713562), (-3.419852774, -0.663090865), (-3.419480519, -0.654939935)],
                knots=[0, 0, 0, 0, 0.971358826, 1.931731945, 2.920909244, 4, 4, 4, 4], degree=3))
            add(Edge.make_bspline(
                [(-3.419480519, -0.654939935), (-3.419734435, -0.648142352), (-3.420223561, -0.635047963), (-3.42568844, -0.616676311), (-3.434446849, -0.600568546), (-3.446731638, -0.587269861), (-3.461381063, -0.576373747), (-3.47836993, -0.568640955), (-3.497335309, -0.563965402), (-3.510645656, -0.563500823), (-3.51755276, -0.56325974)],
                knots=[0, 0, 0, 0, 1.075989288, 2.072710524, 3.011158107, 3.962007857, 4.922430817, 5.890791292, 6.905473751, 8, 8, 8, 8], degree=3))
            add(Edge.make_bspline(
                [(-3.51755276, -0.56325974), (-3.524530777, -0.563593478), (-3.538226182, -0.564248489), (-3.558053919, -0.569982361), (-3.576348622, -0.579420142), (-3.592872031, -0.592571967), (-3.607444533, -0.609089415), (-3.618300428, -0.629724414), (-3.626333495, -0.653649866), (-3.62865061, -0.671007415), (-3.62987013, -0.680142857)],
                knots=[0, 0, 0, 0, 0.93222934, 1.829639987, 2.736832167, 3.670661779, 4.640842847, 5.66155494, 6.769254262, 8, 8, 8, 8], degree=3))
            Line((-3.62987013, -0.680142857), (-3.781818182, -0.656766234))
            add(Edge.make_bspline(
                [(-3.781818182, -0.656766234), (-3.779692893, -0.646873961), (-3.775552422, -0.627601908), (-3.767390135, -0.599955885), (-3.757422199, -0.574515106), (-3.746403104, -0.551014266), (-3.733708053, -0.529694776), (-3.719678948, -0.510402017), (-3.704023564, -0.493291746), (-3.686987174, -0.478244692), (-3.668526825, -0.465246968), (-3.648997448, -0.453873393), (-3.628217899, -0.444410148), (-3.606392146, -0.436441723), (-3.583307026, -0.43052877), (-3.559150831, -0.426097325), (-3.533861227, -0.423553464), (-3.516645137, -0.423186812), (-3.507873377, -0.423)],
                knots=[0, 0, 0, 0, 1.222838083, 2.38232415, 3.479687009, 4.52311912, 5.516350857, 6.474533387, 7.401694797, 8.314107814, 9.21661468, 10.126650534, 11.042026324, 11.973150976, 12.931644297, 13.918942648, 14.939681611, 16, 16, 16, 16], degree=3))
            add(Edge.make_bspline(
                [(-3.507873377, -0.423), (-3.498002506, -0.423201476), (-3.478751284, -0.423594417), (-3.450691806, -0.426908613), (-3.424211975, -0.432479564), (-3.399137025, -0.439750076), (-3.375749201, -0.449784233), (-3.353972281, -0.461848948), (-3.333623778, -0.47600992), (-3.315230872, -0.492356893), (-3.298819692, -0.510063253), (-3.283996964, -0.528049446), (-3.271792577, -0.546803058), (-3.261533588, -0.565844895), (-3.253920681, -0.585589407), (-3.248150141, -0.605665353), (-3.244795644, -0.626276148), (-3.24436956, -0.640135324), (-3.244155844, -0.647086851)],
                knots=[0, 0, 0, 0, 1.230769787, 2.400378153, 3.517119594, 4.602822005, 5.650564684, 6.683681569, 7.703094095, 8.735848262, 9.74563128, 10.71198263, 11.638503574, 12.531701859, 13.404401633, 14.272067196, 15.133298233, 16, 16, 16, 16], degree=3))
            add(Edge.make_bspline(
                [(-3.244155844, -0.647086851), (-3.244507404, -0.656439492), (-3.245200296, -0.674872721), (-3.251767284, -0.701716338), (-3.261982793, -0.727239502), (-3.276722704, -0.751147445), (-3.295322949, -0.773684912), (-3.318454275, -0.794243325), (-3.345098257, -0.81405529), (-3.365210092, -0.825086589), (-3.375649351, -0.8308125)],
                knots=[0, 0, 0, 0, 0.939706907, 1.852079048, 2.764430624, 3.6963375, 4.66659835, 5.694335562, 6.803220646, 8, 8, 8, 8], degree=3))
            add(Edge.make_bspline(
                [(-3.375649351, -0.8308125), (-3.369586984, -0.832274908), (-3.357604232, -0.835165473), (-3.340460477, -0.84154161), (-3.324067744, -0.848843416), (-3.308535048, -0.857351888), (-3.29399367, -0.867429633), (-3.28016484, -0.878432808), (-3.267208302, -0.890846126), (-3.255332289, -0.904477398), (-3.244190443, -0.918982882), (-3.235026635, -0.93483279), (-3.226867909, -0.951304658), (-3.220239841, -0.968713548), (-3.215411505, -0.987112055), (-3.211732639, -1.006262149), (-3.209483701, -1.026355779), (-3.209223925, -1.040039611), (-3.209090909, -1.047046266)],
                knots=[0, 0, 0, 0, 1.008493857, 1.993368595, 2.954750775, 3.911730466, 4.854556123, 5.81472584, 6.769420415, 7.753752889, 8.739021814, 9.724142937, 10.711183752, 11.712141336, 12.73269162, 13.785823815, 14.86625554, 16, 16, 16, 16], degree=3))
            add(Edge.make_bspline(
                [(-3.209090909, -1.047046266), (-3.209288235, -1.05723024), (-3.209675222, -1.077202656), (-3.21414698, -1.106407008), (-3.220724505, -1.134391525), (-3.230584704, -1.160942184), (-3.242776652, -1.186302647), (-3.257916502, -1.210253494), (-3.275883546, -1.232709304), (-3.296321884, -1.253535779), (-3.318320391, -1.27264947), (-3.34191994, -1.289109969), (-3.366376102, -1.303357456), (-3.392128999, -1.314587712), (-3.418728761, -1.323688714), (-3.446452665, -1.33002542), (-3.475190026, -1.33397571), (-3.494711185, -1.334448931), (-3.504586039, -1.334688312)],
                knots=[0, 0, 0, 0, 1.062416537, 2.08357036, 3.077923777, 4.059209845, 5.034279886, 6.011233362, 7.010854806, 8.03119724, 9.05430762, 10.04888448, 11.031219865, 12.00444434, 12.977295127, 13.96252575, 14.969335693, 16, 16, 16, 16], degree=3))
            add(Edge.make_bspline(
                [(-3.504586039, -1.334688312), (-3.514030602, -1.334471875), (-3.532606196, -1.334046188), (-3.55990502, -1.330865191), (-3.586108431, -1.325772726), (-3.6112699, -1.31869183), (-3.63525798, -1.309300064), (-3.658186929, -1.297952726), (-3.679998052, -1.28455035), (-3.700585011, -1.269275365), (-3.719614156, -1.252204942), (-3.736429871, -1.233236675), (-3.751365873, -1.212946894), (-3.763912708, -1.190975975), (-3.774875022, -1.167813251), (-3.783132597, -1.142933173), (-3.789677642, -1.116684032), (-3.792211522, -1.098517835), (-3.793506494, -1.089233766)],
                knots=[0, 0, 0, 0, 1.083411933, 2.130857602, 3.148610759, 4.143507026, 5.125373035, 6.099933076, 7.075018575, 8.058448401, 9.037577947, 10.002175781, 10.961931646, 11.922703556, 12.90078625, 13.896932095, 14.925200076, 16, 16, 16, 16], degree=3))
        make_face()
    # profile 3 of 13: a face of its own
    with BuildSketch(Plane.XZ.offset(3.05)):
        with BuildLine():
            Line((-2.58961039, -1.323), (-2.764935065, -1.323))
            Line((-2.764935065, -1.323), (-2.764935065, -0.668454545))
            add(Edge.make_bspline(
                [(-2.764935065, -0.668454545), (-2.77301585, -0.675607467), (-2.789122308, -0.689864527), (-2.814629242, -0.709600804), (-2.841022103, -0.727843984), (-2.868494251, -0.744497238), (-2.896614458, -0.760044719), (-2.925842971, -0.773957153), (-2.955947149, -0.786437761), (-2.976622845, -0.793484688), (-2.987012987, -0.797025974)],
                knots=[0, 0, 0, 0, 1.001509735, 1.996189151, 2.991510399, 3.978083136, 4.977007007, 5.972841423, 6.981293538, 8, 8, 8, 8], degree=3))
            Line((-2.987012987, -0.797025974), (-2.987012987, -0.645077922))
            add(Edge.make_bspline(
                [(-2.987012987, -0.645077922), (-2.974739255, -0.640626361), (-2.949480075, -0.631465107), (-2.912251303, -0.612610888), (-2.87447125, -0.589286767), (-2.843151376, -0.566639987), (-2.818653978, -0.546622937), (-2.801460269, -0.530700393), (-2.785645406, -0.514239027), (-2.771454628, -0.497126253), (-2.758727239, -0.479411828), (-2.747446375, -0.461260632), (-2.737585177, -0.442489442), (-2.732321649, -0.429500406), (-2.7296875, -0.423)],
                knots=[0, 0, 0, 0, 1.342253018, 2.762339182, 4.28336265, 5.906997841, 6.73458361, 7.536776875, 8.316428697, 9.08145313, 9.821906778, 10.558829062, 11.278761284, 12, 12, 12, 12], degree=3))
            Line((-2.7296875, -0.423), (-2.58961039, -0.423))
            Line((-2.58961039, -0.423), (-2.58961039, -1.323))
        make_face()
    # profile 4 of 13: a face of its own
    with BuildSketch(Plane.XZ.offset(3.05)):
        with Locations((-2.116233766, -0.989883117)):
            Rectangle(SKETCH15_W, SKETCH15_H)
    # profile 5 of 13: a face of its own
    with BuildSketch(Plane.XZ.offset(3.05)):
        with BuildLine():
            Line((-1.338961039, -1.323), (-1.514285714, -1.323))
            Line((-1.514285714, -1.323), (-1.514285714, -0.668454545))
            add(Edge.make_bspline(
                [(-1.514285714, -0.668454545), (-1.522366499, -0.675607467), (-1.538472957, -0.689864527), (-1.563979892, -0.709600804), (-1.590372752, -0.727843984), (-1.6178449, -0.744497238), (-1.645965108, -0.760044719), (-1.67519362, -0.773957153), (-1.705297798, -0.786437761), (-1.725973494, -0.793484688), (-1.736363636, -0.797025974)],
                knots=[0, 0, 0, 0, 1.001509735, 1.996189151, 2.991510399, 3.978083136, 4.977007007, 5.972841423, 6.981293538, 8, 8, 8, 8], degree=3))
            Line((-1.736363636, -0.797025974), (-1.736363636, -0.645077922))
            add(Edge.make_bspline(
                [(-1.736363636, -0.645077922), (-1.724089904, -0.640626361), (-1.698830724, -0.631465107), (-1.661601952, -0.612610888), (-1.6238219, -0.589286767), (-1.592502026, -0.566639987), (-1.568004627, -0.546622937), (-1.550810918, -0.530700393), (-1.534996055, -0.514239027), (-1.520805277, -0.497126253), (-1.508077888, -0.479411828), (-1.496797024, -0.461260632), (-1.486935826, -0.442489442), (-1.481672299, -0.429500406), (-1.479038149, -0.423)],
                knots=[0, 0, 0, 0, 1.342253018, 2.762339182, 4.28336265, 5.906997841, 6.73458361, 7.536776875, 8.316428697, 9.08145313, 9.821906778, 10.558829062, 11.278761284, 12, 12, 12, 12], degree=3))
            Line((-1.479038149, -0.423), (-1.338961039, -0.423))
            Line((-1.338961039, -0.423), (-1.338961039, -1.323))
        make_face()
    # profile 6 of 13: a face of its own
    with BuildSketch(Plane.XZ.offset(3.05)):
        with Locations((-0.865584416, -0.989883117)):
            Rectangle(SKETCH15_W_2, SKETCH15_H)
    # profile 7 of 13: a face of its own
    with BuildSketch(Plane.XZ.offset(3.05)):
        Polygon((0.297402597, -1.323), (0.101075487, -1.323), (0.031310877, -1.124298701), (-0.312581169, -1.124298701), (-0.382345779, -1.323), (-0.579220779, -1.323), (-0.251034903, -0.423), (-0.031513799, -0.423), align=None)
        Polygon((-0.022199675, -0.972350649), (-0.140909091, -0.635033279), (-0.259253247, -0.972350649), align=None, mode=Mode.SUBTRACT)
    # profile 8 of 13: a face of its own
    with BuildSketch(Plane.XZ.offset(3.05)):
        with Locations((0.583766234, -0.989883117)):
            Rectangle(SKETCH15_W, SKETCH15_H)
    # profile 9 of 13: a face of its own
    with BuildSketch(Plane.XZ.offset(3.05)):
        Polygon((0.87012987, -1.323), (1.173112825, -0.84542289), (0.905194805, -0.423), (1.117593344, -0.423), (1.279220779, -0.677951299), (1.440848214, -0.423), (1.653246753, -0.423), (1.385511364, -0.84542289), (1.688311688, -1.323), (1.475913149, -1.323), (1.279220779, -1.012894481), (1.082528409, -1.323), align=None)
    # profile 10 of 13: a face of its own
    with BuildSketch(Plane.XZ.offset(3.05)):
        Polygon((1.758441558, -1.334688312), (1.965726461, -0.411311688), (2.109090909, -0.411311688), (1.901806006, -1.334688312), align=None)
    # profile 11 of 13: a face of its own
    with BuildSketch(Plane.XZ.offset(3.05)):
        with BuildLine():
            Line((2.681818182, -1.323), (2.506493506, -1.323))
            Line((2.506493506, -1.323), (2.506493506, -0.668454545))
            add(Edge.make_bspline(
                [(2.506493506, -0.668454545), (2.498412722, -0.675607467), (2.482306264, -0.689864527), (2.456799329, -0.709600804), (2.430406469, -0.727843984), (2.40293432, -0.744497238), (2.374814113, -0.760044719), (2.345585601, -0.773957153), (2.315481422, -0.786437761), (2.294805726, -0.793484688), (2.284415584, -0.797025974)],
                knots=[0, 0, 0, 0, 1.001509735, 1.996189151, 2.991510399, 3.978083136, 4.977007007, 5.972841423, 6.981293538, 8, 8, 8, 8], degree=3))
            Line((2.284415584, -0.797025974), (2.284415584, -0.645077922))
            add(Edge.make_bspline(
                [(2.284415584, -0.645077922), (2.296689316, -0.640626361), (2.321948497, -0.631465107), (2.359177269, -0.612610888), (2.396957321, -0.589286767), (2.428277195, -0.566639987), (2.452774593, -0.546622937), (2.469968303, -0.530700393), (2.485783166, -0.514239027), (2.499973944, -0.497126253), (2.512701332, -0.479411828), (2.523982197, -0.461260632), (2.533843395, -0.442489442), (2.539106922, -0.429500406), (2.541741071, -0.423)],
                knots=[0, 0, 0, 0, 1.342253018, 2.762339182, 4.28336265, 5.906997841, 6.73458361, 7.536776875, 8.316428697, 9.08145313, 9.821906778, 10.558829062, 11.278761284, 12, 12, 12, 12], degree=3))
            Line((2.541741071, -0.423), (2.681818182, -0.423))
            Line((2.681818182, -0.423), (2.681818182, -1.323))
        make_face()
    # profile 12 of 13: a face of its own
    with BuildSketch(Plane.XZ.offset(3.05)):
        with BuildLine():
            Line((3.044155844, -0.423), (3.367775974, -0.423))
            add(Edge.make_bspline(
                [(3.367775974, -0.423), (3.377699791, -0.423066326), (3.39688423, -0.423194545), (3.424780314, -0.424285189), (3.45077646, -0.426150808), (3.474929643, -0.428367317), (3.497107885, -0.431679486), (3.517378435, -0.435732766), (3.535935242, -0.44013426), (3.558101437, -0.44752553), (3.584128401, -0.459033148), (3.613765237, -0.476518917), (3.641992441, -0.498120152), (3.668883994, -0.523514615), (3.69379885, -0.552983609), (3.715969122, -0.586642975), (3.735095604, -0.624444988), (3.748711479, -0.658683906), (3.757742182, -0.688285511), (3.764045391, -0.712002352), (3.769081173, -0.737146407), (3.773267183, -0.763591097), (3.776515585, -0.791375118), (3.778937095, -0.820426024), (3.780118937, -0.850831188), (3.78038392, -0.871538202), (3.780519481, -0.882131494)],
                knots=[0, 0, 0, 0, 1.002944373, 1.938863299, 2.820829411, 3.636897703, 4.389550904, 5.085770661, 5.725933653, 6.315457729, 7.444919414, 8.595071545, 9.785001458, 11.029737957, 12.326413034, 13.676197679, 15.093293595, 16.601413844, 17.393472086, 18.220208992, 19.080535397, 19.98381144, 20.92553657, 21.907059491, 22.929293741, 24, 24, 24, 24], degree=3))
            add(Edge.make_bspline(
                [(3.780519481, -0.882131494), (3.780143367, -0.900958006), (3.779414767, -0.937428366), (3.773540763, -0.990288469), (3.763802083, -1.039394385), (3.750133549, -1.084553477), (3.73328924, -1.125364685), (3.714550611, -1.162042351), (3.693566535, -1.194195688), (3.67029743, -1.222076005), (3.644533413, -1.245838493), (3.616504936, -1.266517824), (3.585948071, -1.284080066), (3.558416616, -1.29591339), (3.535063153, -1.303927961), (3.516069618, -1.309009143), (3.495961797, -1.313368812), (3.474556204, -1.316818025), (3.452010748, -1.319522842), (3.42819272, -1.321501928), (3.40316091, -1.322854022), (3.386040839, -1.322950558), (3.377272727, -1.323)],
                knots=[0, 0, 0, 0, 1.650744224, 3.197790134, 4.65735313, 6.035495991, 7.328331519, 8.524635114, 9.642607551, 10.688473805, 11.700911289, 12.708919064, 13.737320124, 14.784657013, 15.331672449, 15.901528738, 16.507833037, 17.135390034, 17.802231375, 18.498759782, 19.23113397, 20, 20, 20, 20], degree=3))
            Line((3.377272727, -1.323), (3.044155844, -1.323))
            Line((3.044155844, -1.323), (3.044155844, -0.423))
        make_face()
        with BuildLine():
            Line((3.219480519, -0.574948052), (3.219480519, -1.171051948))
            Line((3.219480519, -1.171051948), (3.351704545, -1.171051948))
            add(Edge.make_bspline(
                [(3.351704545, -1.171051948), (3.358524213, -1.171045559), (3.371741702, -1.171033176), (3.390788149, -1.170129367), (3.408418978, -1.169479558), (3.424465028, -1.167630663), (3.439180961, -1.165966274), (3.452400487, -1.163584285), (3.464176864, -1.160876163), (3.477755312, -1.156791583), (3.492947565, -1.150321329), (3.509561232, -1.140955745), (3.524520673, -1.129973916), (3.537935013, -1.116796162), (3.549855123, -1.100628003), (3.560388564, -1.080784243), (3.569742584, -1.057098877), (3.578117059, -1.029443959), (3.585377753, -0.997521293), (3.58993676, -0.960828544), (3.59317227, -0.919567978), (3.593391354, -0.890479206), (3.593506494, -0.875191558)],
                knots=[0, 0, 0, 0, 0.904785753, 1.753603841, 2.530154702, 3.24473756, 3.896016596, 4.49499724, 5.026007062, 5.498767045, 6.374936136, 7.210582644, 8.024871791, 8.830297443, 9.696278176, 10.679455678, 11.803011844, 13.070427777, 14.510895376, 16.141175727, 17.971989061, 20, 20, 20, 20], degree=3))
            add(Edge.make_bspline(
                [(3.593506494, -0.875191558), (3.59350589, -0.867093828), (3.593504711, -0.851257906), (3.592497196, -0.828244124), (3.591203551, -0.806510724), (3.589713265, -0.786142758), (3.587266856, -0.767025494), (3.584385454, -0.749303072), (3.581106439, -0.732835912), (3.576123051, -0.713062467), (3.568534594, -0.69049336), (3.556995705, -0.666014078), (3.543084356, -0.644649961), (3.526850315, -0.62627581), (3.508396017, -0.611122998), (3.488292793, -0.598468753), (3.466182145, -0.588819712), (3.450456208, -0.584949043), (3.442471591, -0.582983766)],
                knots=[0, 0, 0, 0, 1.07961287, 2.111290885, 3.070799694, 3.982852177, 4.833606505, 5.639620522, 6.376674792, 7.071628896, 8.357654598, 9.544898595, 10.670582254, 11.745761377, 12.800648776, 13.843474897, 14.905055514, 16, 16, 16, 16], degree=3))
            add(Edge.make_bspline(
                [(3.442471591, -0.582983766), (3.439006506, -0.582344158), (3.431434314, -0.580946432), (3.418933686, -0.57938287), (3.404326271, -0.577878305), (3.387506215, -0.57689737), (3.368515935, -0.575915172), (3.347322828, -0.575465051), (3.324007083, -0.575076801), (3.307751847, -0.57499213), (3.299289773, -0.574948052)],
                knots=[0, 0, 0, 0, 0.588836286, 1.286774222, 2.104838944, 3.042933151, 4.102361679, 5.283063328, 6.58563002, 8, 8, 8, 8], degree=3))
            Line((3.299289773, -0.574948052), (3.219480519, -0.574948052))
        make_face(mode=Mode.SUBTRACT)
    # profile 13 of 13: a face of its own
    with BuildSketch(Plane.XZ.offset(3.05)):
        with BuildLine():
            Line((4.002597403, -1.323), (4.002597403, -0.423))
            Line((4.002597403, -0.423), (4.373153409, -0.423))
            add(Edge.make_bspline(
                [(4.373153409, -0.423), (4.38459863, -0.423072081), (4.406642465, -0.423210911), (4.438442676, -0.424208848), (4.467659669, -0.426327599), (4.494371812, -0.428698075), (4.518497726, -0.43219182), (4.540092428, -0.436322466), (4.559155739, -0.441179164), (4.581132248, -0.448682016), (4.605851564, -0.46091471), (4.632502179, -0.480084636), (4.656509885, -0.503506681), (4.67361792, -0.526547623), (4.685656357, -0.546752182), (4.693734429, -0.562833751), (4.70050839, -0.579695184), (4.70597083, -0.59736525), (4.710354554, -0.615722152), (4.713460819, -0.634885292), (4.715313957, -0.654719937), (4.715493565, -0.668207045), (4.715584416, -0.675029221)],
                knots=[0, 0, 0, 0, 1.403495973, 2.7031748, 3.900391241, 4.995277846, 5.990810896, 6.888255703, 7.690350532, 8.400936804, 9.73299162, 11.054630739, 12.411307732, 13.829654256, 14.559392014, 15.293849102, 16.03408777, 16.784903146, 17.559860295, 18.346522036, 19.16362217, 20, 20, 20, 20], degree=3))
            add(Edge.make_bspline(
                [(4.715584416, -0.675029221), (4.715434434, -0.683622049), (4.715140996, -0.700433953), (4.712103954, -0.724985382), (4.707401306, -0.748270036), (4.700858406, -0.770326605), (4.692247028, -0.79108899), (4.681584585, -0.81051313), (4.669104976, -0.828685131), (4.654834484, -0.845561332), (4.638679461, -0.860923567), (4.620891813, -0.874782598), (4.601659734, -0.887343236), (4.580627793, -0.898026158), (4.558176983, -0.907634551), (4.533929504, -0.915377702), (4.508186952, -0.921826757), (4.490365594, -0.924806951), (4.481270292, -0.926327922)],
                knots=[0, 0, 0, 0, 1.08409468, 2.12103565, 3.117116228, 4.079769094, 5.020146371, 5.948581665, 6.871435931, 7.798216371, 8.732989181, 9.679842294, 10.641052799, 11.627364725, 12.653459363, 13.720177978, 14.836470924, 16, 16, 16, 16], degree=3))
            add(Edge.make_bspline(
                [(4.481270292, -0.926327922), (4.49072102, -0.931991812), (4.509127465, -0.943022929), (4.534805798, -0.961156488), (4.557852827, -0.980170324), (4.575532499, -0.997059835), (4.589006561, -1.012038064), (4.599760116, -1.025225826), (4.61122461, -1.040470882), (4.623707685, -1.057617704), (4.636763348, -1.07698952), (4.650644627, -1.098360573), (4.665282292, -1.121823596), (4.675184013, -1.138226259), (4.680336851, -1.146762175)],
                knots=[0, 0, 0, 0, 1.316598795, 2.564236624, 3.753007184, 4.885112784, 5.482740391, 6.160057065, 6.918254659, 7.762424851, 8.694807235, 9.70996768, 10.808271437, 12, 12, 12, 12], degree=3))
            Line((4.680336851, -1.146762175), (4.785714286, -1.323))
            Line((4.785714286, -1.323), (4.563453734, -1.323))
            Line((4.563453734, -1.323), (4.438717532, -1.129229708))
            add(Edge.make_bspline(
                [(4.438717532, -1.129229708), (4.433300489, -1.120889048), (4.422972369, -1.104986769), (4.408251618, -1.082353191), (4.394792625, -1.062186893), (4.382970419, -1.044309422), (4.371980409, -1.029160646), (4.362853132, -1.016132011), (4.354759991, -1.005742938), (4.346207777, -0.99514688), (4.336160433, -0.984419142), (4.323845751, -0.973791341), (4.311005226, -0.965386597), (4.297289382, -0.958845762), (4.281223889, -0.95417562), (4.261858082, -0.951078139), (4.238522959, -0.949418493), (4.221694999, -0.949129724), (4.212621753, -0.948974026)],
                knots=[0, 0, 0, 0, 1.540704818, 2.937503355, 4.182537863, 5.296801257, 6.257162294, 7.081582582, 7.760660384, 8.296803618, 9.190784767, 10.033661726, 10.810538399, 11.561451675, 12.378938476, 13.39290606, 14.594315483, 16, 16, 16, 16], degree=3))
            Line((4.212621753, -0.948974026), (4.177922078, -0.948974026))
            Line((4.177922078, -0.948974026), (4.177922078, -1.323))
            Line((4.177922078, -1.323), (4.002597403, -1.323))
        make_face()
        with BuildLine():
            Line((4.177922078, -0.797025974), (4.306493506, -0.797025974))
            add(Edge.make_bspline(
                [(4.306493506, -0.797025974), (4.315868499, -0.796975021), (4.333706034, -0.796878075), (4.359156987, -0.796585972), (4.381925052, -0.795822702), (4.402016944, -0.794927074), (4.419440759, -0.793896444), (4.434195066, -0.792508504), (4.446261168, -0.790705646), (4.458681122, -0.788148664), (4.471786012, -0.783452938), (4.48566587, -0.775645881), (4.498163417, -0.765827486), (4.508985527, -0.753702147), (4.517853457, -0.739276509), (4.524275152, -0.722653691), (4.52788201, -0.703794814), (4.528333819, -0.690568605), (4.528571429, -0.683612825)],
                knots=[0, 0, 0, 0, 1.561361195, 2.970757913, 4.238718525, 5.355104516, 6.320180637, 7.145394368, 7.822172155, 8.35112574, 9.25544315, 10.126941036, 10.993055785, 11.890584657, 12.819129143, 13.798163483, 14.842034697, 16, 16, 16, 16], degree=3))
            add(Edge.make_bspline(
                [(4.528571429, -0.683612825), (4.528325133, -0.676962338), (4.527853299, -0.664221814), (4.524313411, -0.64606525), (4.517808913, -0.630068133), (4.508921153, -0.616225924), (4.498014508, -0.604296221), (4.48500094, -0.594686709), (4.470483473, -0.586526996), (4.459738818, -0.583216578), (4.454241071, -0.581522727)],
                knots=[0, 0, 0, 0, 1.164790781, 2.231422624, 3.22158524, 4.171176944, 5.099451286, 6.035776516, 6.9949606, 8, 8, 8, 8], degree=3))
            add(Edge.make_bspline(
                [(4.454241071, -0.581522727), (4.451749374, -0.581012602), (4.445824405, -0.579799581), (4.435405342, -0.578373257), (4.422108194, -0.577408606), (4.405974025, -0.576483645), (4.386976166, -0.575801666), (4.365060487, -0.57519902), (4.340279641, -0.575151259), (4.322808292, -0.575018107), (4.313616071, -0.574948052)],
                knots=[0, 0, 0, 0, 0.432971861, 1.029557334, 1.788740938, 2.702316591, 3.781055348, 5.025222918, 6.434877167, 8, 8, 8, 8], degree=3))
            Line((4.313616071, -0.574948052), (4.177922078, -0.574948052))
            Line((4.177922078, -0.574948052), (4.177922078, -0.797025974))
        make_face(mode=Mode.SUBTRACT)
    extrude(amount=PART_NUMBER_DEPTH)

    # Sketch2 → Boss-Extrude11 (add)
    with BuildSketch(Plane(origin=(0, 3.05, 0), x_dir=(1, 0, 0), z_dir=(0, 1, 0))):
        with Locations(Location((-5.7, 1.3, 0), (0, 0, 270))):
            Circle(SKETCH2_R)
    boss_extrude11 = extrude(amount=BOSS_EXTRUDE11_DEPTH)

    # Mirror1: Boss-Extrude11 across plane
    add(boss_extrude11.mirror(Plane(origin=(0, 0, 0), x_dir=(0, 0, 1), z_dir=(1, 0, 0))))

    # Mirror2: Boss-Extrude11 across plane
    add(boss_extrude11.mirror(Plane.XY))

    # Mirror2 copy 1 sketch → Mirror2 copy 1 (add)
    with BuildSketch(Plane(origin=(0, 3.05, 0), x_dir=(-1, 0, 0), z_dir=(0, 1, 0))):
        with Locations(Location((-5.7, 1.3, 0), (0, 0, 270))):
            Circle(MIRROR2_COPY_1_SKETCH_R)
    extrude(amount=MIRROR2_COPY_1_DEPTH)

    # Sketch16 → Boss-Extrude12 (add)
    with BuildSketch(Plane(origin=(0, 3.05, 0), x_dir=(1, 0, 0), z_dir=(0, 1, 0))):
        with Locations((1.016, 0)):
            Rectangle(SKETCH16_W, SKETCH16_H)
        with Locations((5.08, 0)):
            Rectangle(SKETCH16_W, SKETCH16_H)
        with Locations((-1.016, 0)):
            Rectangle(SKETCH16_W, SKETCH16_H)
        with Locations((-5.08, 0)):
            Rectangle(SKETCH16_W, SKETCH16_H)
    extrude(amount=BOSS_EXTRUDE12_DEPTH)


solid = part.part
